VERSION 5.7 ;
  NOWIREEXTENSIONATPIN ON ;
  DIVIDERCHAR "/" ;
  BUSBITCHARS "[]" ;
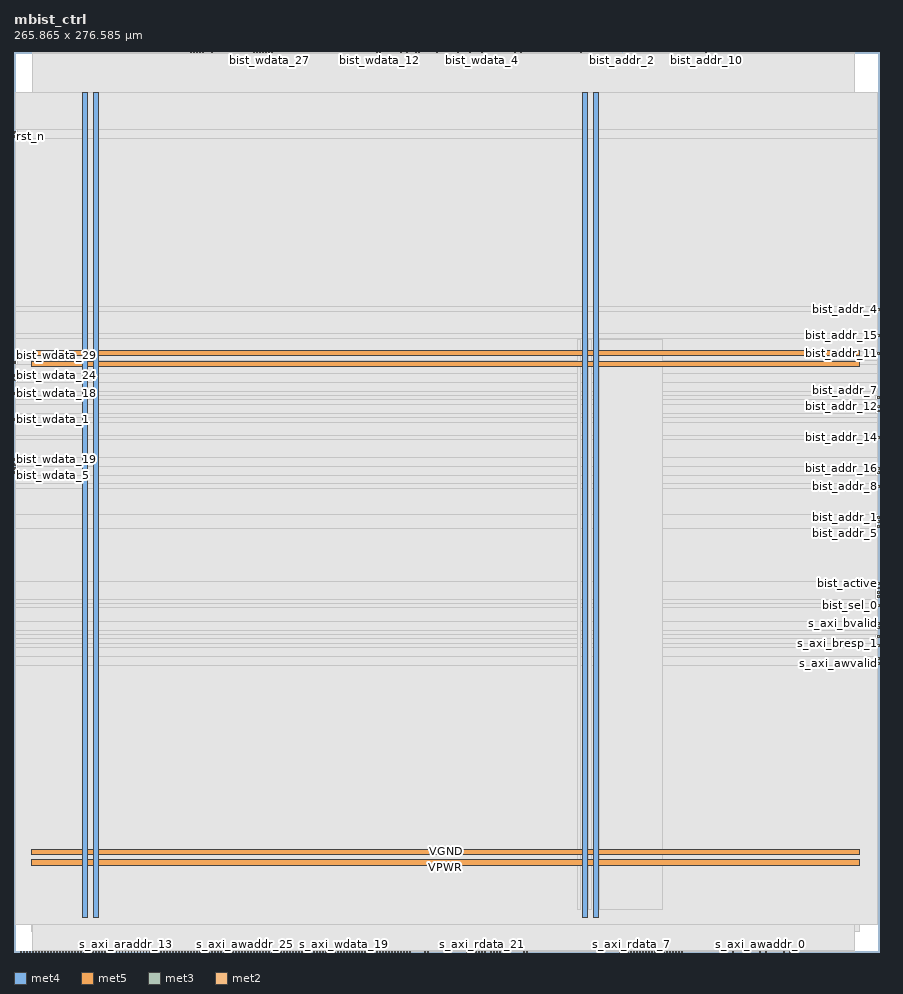
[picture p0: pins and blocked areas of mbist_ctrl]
MACRO mbist_ctrl
  CLASS BLOCK ;
  FOREIGN mbist_ctrl ;
  ORIGIN 0.000 0.000 ;
  SIZE 265.865 BY 276.585 ;
  PIN VGND
    DIRECTION INOUT ;
    USE GROUND ;
    PORT
      LAYER met4 ;
        RECT 24.340 10.640 25.940 264.080 ;
    END
    PORT
      LAYER met4 ;
        RECT 177.940 10.640 179.540 264.080 ;
    END
    PORT
      LAYER met5 ;
        RECT 5.520 30.030 259.900 31.630 ;
    END
    PORT
      LAYER met5 ;
        RECT 5.520 183.210 259.900 184.810 ;
    END
  END VGND
  PIN VPWR
    DIRECTION INOUT ;
    USE POWER ;
    PORT
      LAYER met4 ;
        RECT 21.040 10.640 22.640 264.080 ;
    END
    PORT
      LAYER met4 ;
        RECT 174.640 10.640 176.240 264.080 ;
    END
    PORT
      LAYER met5 ;
        RECT 5.520 26.730 259.900 28.330 ;
    END
    PORT
      LAYER met5 ;
        RECT 5.520 179.910 259.900 181.510 ;
    END
  END VPWR
  PIN bist_active
    DIRECTION OUTPUT ;
    USE SIGNAL ;
    ANTENNAGATEAREA 0.434700 ;
    ANTENNADIFFAREA 1.137600 ;
    PORT
      LAYER met3 ;
        RECT 265.265 112.920 265.865 113.520 ;
    END
  END bist_active
  PIN bist_addr_0
    DIRECTION OUTPUT ;
    USE SIGNAL ;
    ANTENNAGATEAREA 0.434700 ;
    ANTENNADIFFAREA 1.137600 ;
    PORT
      LAYER met3 ;
        RECT 265.265 146.920 265.865 147.520 ;
    END
  END bist_addr_0
  PIN bist_addr_1
    DIRECTION OUTPUT ;
    USE SIGNAL ;
    ANTENNAGATEAREA 0.434700 ;
    ANTENNADIFFAREA 1.137600 ;
    PORT
      LAYER met3 ;
        RECT 265.265 133.320 265.865 133.920 ;
    END
  END bist_addr_1
  PIN bist_addr_10
    DIRECTION OUTPUT ;
    USE SIGNAL ;
    ANTENNAGATEAREA 0.434700 ;
    ANTENNADIFFAREA 1.137600 ;
    PORT
      LAYER met2 ;
        RECT 212.610 276.305 212.890 276.585 ;
    END
  END bist_addr_10
  PIN bist_addr_11
    DIRECTION OUTPUT ;
    USE SIGNAL ;
    ANTENNAGATEAREA 0.434700 ;
    ANTENNADIFFAREA 1.137600 ;
    PORT
      LAYER met3 ;
        RECT 265.265 183.640 265.865 184.240 ;
    END
  END bist_addr_11
  PIN bist_addr_12
    DIRECTION OUTPUT ;
    USE SIGNAL ;
    ANTENNAGATEAREA 0.434700 ;
    ANTENNADIFFAREA 1.137600 ;
    PORT
      LAYER met3 ;
        RECT 265.265 167.320 265.865 167.920 ;
    END
  END bist_addr_12
  PIN bist_addr_13
    DIRECTION OUTPUT ;
    USE SIGNAL ;
    ANTENNAGATEAREA 0.434700 ;
    ANTENNADIFFAREA 1.137600 ;
    PORT
      LAYER met3 ;
        RECT 265.265 131.960 265.865 132.560 ;
    END
  END bist_addr_13
  PIN bist_addr_14
    DIRECTION OUTPUT ;
    USE SIGNAL ;
    ANTENNAGATEAREA 0.434700 ;
    ANTENNADIFFAREA 1.137600 ;
    PORT
      LAYER met3 ;
        RECT 265.265 157.800 265.865 158.400 ;
    END
  END bist_addr_14
  PIN bist_addr_15
    DIRECTION OUTPUT ;
    USE SIGNAL ;
    ANTENNAGATEAREA 0.434700 ;
    ANTENNADIFFAREA 1.137600 ;
    PORT
      LAYER met3 ;
        RECT 265.265 189.080 265.865 189.680 ;
    END
  END bist_addr_15
  PIN bist_addr_16
    DIRECTION OUTPUT ;
    USE SIGNAL ;
    ANTENNAGATEAREA 0.434700 ;
    ANTENNADIFFAREA 1.137600 ;
    PORT
      LAYER met3 ;
        RECT 265.265 148.280 265.865 148.880 ;
    END
  END bist_addr_16
  PIN bist_addr_17
    DIRECTION OUTPUT ;
    USE SIGNAL ;
    ANTENNAGATEAREA 0.434700 ;
    ANTENNADIFFAREA 1.137600 ;
    PORT
      LAYER met2 ;
        RECT 155.570 276.305 155.850 276.585 ;
    END
  END bist_addr_17
  PIN bist_addr_2
    DIRECTION OUTPUT ;
    USE SIGNAL ;
    ANTENNAGATEAREA 0.434700 ;
    ANTENNADIFFAREA 1.137600 ;
    PORT
      LAYER met2 ;
        RECT 186.850 276.305 187.130 276.585 ;
    END
  END bist_addr_2
  PIN bist_addr_3
    DIRECTION OUTPUT ;
    USE SIGNAL ;
    ANTENNAGATEAREA 0.434700 ;
    ANTENNADIFFAREA 1.137600 ;
    PORT
      LAYER met3 ;
        RECT 265.265 165.960 265.865 166.560 ;
    END
  END bist_addr_3
  PIN bist_addr_4
    DIRECTION OUTPUT ;
    USE SIGNAL ;
    ANTENNAGATEAREA 0.434700 ;
    ANTENNADIFFAREA 1.137600 ;
    PORT
      LAYER met3 ;
        RECT 265.265 197.240 265.865 197.840 ;
    END
  END bist_addr_4
  PIN bist_addr_5
    DIRECTION OUTPUT ;
    USE SIGNAL ;
    ANTENNAGATEAREA 0.434700 ;
    ANTENNADIFFAREA 1.137600 ;
    PORT
      LAYER met3 ;
        RECT 265.265 130.600 265.865 131.200 ;
    END
  END bist_addr_5
  PIN bist_addr_6
    DIRECTION OUTPUT ;
    USE SIGNAL ;
    ANTENNAGATEAREA 0.434700 ;
    ANTENNADIFFAREA 1.137600 ;
    PORT
      LAYER met2 ;
        RECT 153.730 276.305 154.010 276.585 ;
    END
  END bist_addr_6
  PIN bist_addr_7
    DIRECTION OUTPUT ;
    USE SIGNAL ;
    ANTENNAGATEAREA 0.434700 ;
    ANTENNADIFFAREA 1.137600 ;
    PORT
      LAYER met3 ;
        RECT 265.265 170.040 265.865 170.640 ;
    END
  END bist_addr_7
  PIN bist_addr_8
    DIRECTION OUTPUT ;
    USE SIGNAL ;
    ANTENNAGATEAREA 0.434700 ;
    ANTENNADIFFAREA 1.137600 ;
    PORT
      LAYER met3 ;
        RECT 265.265 142.840 265.865 143.440 ;
    END
  END bist_addr_8
  PIN bist_addr_9
    DIRECTION OUTPUT ;
    USE SIGNAL ;
    ANTENNAGATEAREA 0.434700 ;
    ANTENNADIFFAREA 1.137600 ;
    PORT
      LAYER met2 ;
        RECT 173.970 276.305 174.250 276.585 ;
    END
  END bist_addr_9
  PIN bist_en
    DIRECTION OUTPUT ;
    USE SIGNAL ;
    ANTENNAGATEAREA 0.434700 ;
    ANTENNADIFFAREA 1.137600 ;
    PORT
      LAYER met2 ;
        RECT 127.050 0.000 127.330 0.280 ;
    END
  END bist_en
  PIN bist_rdata_0
    DIRECTION INPUT ;
    USE SIGNAL ;
    PORT
      LAYER met2 ;
        RECT 1.930 0.000 2.210 0.280 ;
    END
  END bist_rdata_0
  PIN bist_rdata_1
    DIRECTION INPUT ;
    USE SIGNAL ;
    PORT
      LAYER met2 ;
        RECT 2.850 0.000 3.130 0.280 ;
    END
  END bist_rdata_1
  PIN bist_rdata_10
    DIRECTION INPUT ;
    USE SIGNAL ;
    PORT
      LAYER met2 ;
        RECT 3.770 0.000 4.050 0.280 ;
    END
  END bist_rdata_10
  PIN bist_rdata_11
    DIRECTION INPUT ;
    USE SIGNAL ;
    PORT
      LAYER met2 ;
        RECT 4.690 0.000 4.970 0.280 ;
    END
  END bist_rdata_11
  PIN bist_rdata_12
    DIRECTION INPUT ;
    USE SIGNAL ;
    PORT
      LAYER met2 ;
        RECT 5.610 0.000 5.890 0.280 ;
    END
  END bist_rdata_12
  PIN bist_rdata_13
    DIRECTION INPUT ;
    USE SIGNAL ;
    PORT
      LAYER met2 ;
        RECT 6.530 0.000 6.810 0.280 ;
    END
  END bist_rdata_13
  PIN bist_rdata_14
    DIRECTION INPUT ;
    USE SIGNAL ;
    PORT
      LAYER met2 ;
        RECT 7.450 0.000 7.730 0.280 ;
    END
  END bist_rdata_14
  PIN bist_rdata_15
    DIRECTION INPUT ;
    USE SIGNAL ;
    PORT
      LAYER met2 ;
        RECT 8.370 0.000 8.650 0.280 ;
    END
  END bist_rdata_15
  PIN bist_rdata_16
    DIRECTION INPUT ;
    USE SIGNAL ;
    PORT
      LAYER met2 ;
        RECT 9.290 0.000 9.570 0.280 ;
    END
  END bist_rdata_16
  PIN bist_rdata_17
    DIRECTION INPUT ;
    USE SIGNAL ;
    PORT
      LAYER met2 ;
        RECT 10.210 0.000 10.490 0.280 ;
    END
  END bist_rdata_17
  PIN bist_rdata_18
    DIRECTION INPUT ;
    USE SIGNAL ;
    PORT
      LAYER met2 ;
        RECT 11.130 0.000 11.410 0.280 ;
    END
  END bist_rdata_18
  PIN bist_rdata_19
    DIRECTION INPUT ;
    USE SIGNAL ;
    PORT
      LAYER met2 ;
        RECT 12.050 0.000 12.330 0.280 ;
    END
  END bist_rdata_19
  PIN bist_rdata_2
    DIRECTION INPUT ;
    USE SIGNAL ;
    PORT
      LAYER met2 ;
        RECT 12.970 0.000 13.250 0.280 ;
    END
  END bist_rdata_2
  PIN bist_rdata_20
    DIRECTION INPUT ;
    USE SIGNAL ;
    PORT
      LAYER met2 ;
        RECT 13.890 0.000 14.170 0.280 ;
    END
  END bist_rdata_20
  PIN bist_rdata_21
    DIRECTION INPUT ;
    USE SIGNAL ;
    PORT
      LAYER met2 ;
        RECT 14.810 0.000 15.090 0.280 ;
    END
  END bist_rdata_21
  PIN bist_rdata_22
    DIRECTION INPUT ;
    USE SIGNAL ;
    PORT
      LAYER met2 ;
        RECT 15.730 0.000 16.010 0.280 ;
    END
  END bist_rdata_22
  PIN bist_rdata_23
    DIRECTION INPUT ;
    USE SIGNAL ;
    PORT
      LAYER met2 ;
        RECT 16.650 0.000 16.930 0.280 ;
    END
  END bist_rdata_23
  PIN bist_rdata_24
    DIRECTION INPUT ;
    USE SIGNAL ;
    PORT
      LAYER met2 ;
        RECT 17.570 0.000 17.850 0.280 ;
    END
  END bist_rdata_24
  PIN bist_rdata_25
    DIRECTION INPUT ;
    USE SIGNAL ;
    PORT
      LAYER met2 ;
        RECT 18.490 0.000 18.770 0.280 ;
    END
  END bist_rdata_25
  PIN bist_rdata_26
    DIRECTION INPUT ;
    USE SIGNAL ;
    PORT
      LAYER met2 ;
        RECT 19.410 0.000 19.690 0.280 ;
    END
  END bist_rdata_26
  PIN bist_rdata_27
    DIRECTION INPUT ;
    USE SIGNAL ;
    PORT
      LAYER met2 ;
        RECT 20.330 0.000 20.610 0.280 ;
    END
  END bist_rdata_27
  PIN bist_rdata_28
    DIRECTION INPUT ;
    USE SIGNAL ;
    PORT
      LAYER met2 ;
        RECT 21.250 0.000 21.530 0.280 ;
    END
  END bist_rdata_28
  PIN bist_rdata_29
    DIRECTION INPUT ;
    USE SIGNAL ;
    PORT
      LAYER met2 ;
        RECT 22.170 0.000 22.450 0.280 ;
    END
  END bist_rdata_29
  PIN bist_rdata_3
    DIRECTION INPUT ;
    USE SIGNAL ;
    PORT
      LAYER met2 ;
        RECT 23.090 0.000 23.370 0.280 ;
    END
  END bist_rdata_3
  PIN bist_rdata_30
    DIRECTION INPUT ;
    USE SIGNAL ;
    PORT
      LAYER met2 ;
        RECT 24.010 0.000 24.290 0.280 ;
    END
  END bist_rdata_30
  PIN bist_rdata_31
    DIRECTION INPUT ;
    USE SIGNAL ;
    PORT
      LAYER met2 ;
        RECT 24.930 0.000 25.210 0.280 ;
    END
  END bist_rdata_31
  PIN bist_rdata_4
    DIRECTION INPUT ;
    USE SIGNAL ;
    PORT
      LAYER met2 ;
        RECT 25.850 0.000 26.130 0.280 ;
    END
  END bist_rdata_4
  PIN bist_rdata_5
    DIRECTION INPUT ;
    USE SIGNAL ;
    PORT
      LAYER met2 ;
        RECT 26.770 0.000 27.050 0.280 ;
    END
  END bist_rdata_5
  PIN bist_rdata_6
    DIRECTION INPUT ;
    USE SIGNAL ;
    PORT
      LAYER met2 ;
        RECT 27.690 0.000 27.970 0.280 ;
    END
  END bist_rdata_6
  PIN bist_rdata_7
    DIRECTION INPUT ;
    USE SIGNAL ;
    PORT
      LAYER met2 ;
        RECT 28.610 0.000 28.890 0.280 ;
    END
  END bist_rdata_7
  PIN bist_rdata_8
    DIRECTION INPUT ;
    USE SIGNAL ;
    PORT
      LAYER met2 ;
        RECT 29.530 0.000 29.810 0.280 ;
    END
  END bist_rdata_8
  PIN bist_rdata_9
    DIRECTION INPUT ;
    USE SIGNAL ;
    PORT
      LAYER met2 ;
        RECT 30.450 0.000 30.730 0.280 ;
    END
  END bist_rdata_9
  PIN bist_sel_0
    DIRECTION OUTPUT ;
    USE SIGNAL ;
    ANTENNAGATEAREA 0.434700 ;
    ANTENNADIFFAREA 1.137600 ;
    PORT
      LAYER met3 ;
        RECT 265.265 106.120 265.865 106.720 ;
    END
  END bist_sel_0
  PIN bist_sel_1
    DIRECTION OUTPUT ;
    USE SIGNAL ;
    ANTENNAGATEAREA 0.434700 ;
    ANTENNADIFFAREA 1.137600 ;
    PORT
      LAYER met3 ;
        RECT 265.265 110.200 265.865 110.800 ;
    END
  END bist_sel_1
  PIN bist_sel_2
    DIRECTION OUTPUT ;
    USE SIGNAL ;
    ANTENNAGATEAREA 0.434700 ;
    ANTENNADIFFAREA 1.137600 ;
    PORT
      LAYER met3 ;
        RECT 265.265 108.840 265.865 109.440 ;
    END
  END bist_sel_2
  PIN bist_sel_3
    DIRECTION OUTPUT ;
    USE SIGNAL ;
    ANTENNAGATEAREA 0.434700 ;
    ANTENNADIFFAREA 1.137600 ;
    PORT
      LAYER met3 ;
        RECT 265.265 111.560 265.865 112.160 ;
    END
  END bist_sel_3
  PIN bist_wdata_0
    DIRECTION OUTPUT ;
    USE SIGNAL ;
    ANTENNAGATEAREA 0.434700 ;
    ANTENNADIFFAREA 1.137600 ;
    PORT
      LAYER met2 ;
        RECT 129.810 276.305 130.090 276.585 ;
    END
  END bist_wdata_0
  PIN bist_wdata_1
    DIRECTION OUTPUT ;
    USE SIGNAL ;
    ANTENNAGATEAREA 0.434700 ;
    ANTENNADIFFAREA 1.137600 ;
    PORT
      LAYER met3 ;
        RECT 0.000 163.240 0.600 163.840 ;
    END
  END bist_wdata_1
  PIN bist_wdata_10
    DIRECTION OUTPUT ;
    USE SIGNAL ;
    ANTENNAGATEAREA 0.434700 ;
    ANTENNADIFFAREA 1.137600 ;
    PORT
      LAYER met2 ;
        RECT 73.690 276.305 73.970 276.585 ;
    END
  END bist_wdata_10
  PIN bist_wdata_11
    DIRECTION OUTPUT ;
    USE SIGNAL ;
    ANTENNAGATEAREA 0.434700 ;
    ANTENNADIFFAREA 1.137600 ;
    PORT
      LAYER met2 ;
        RECT 136.250 276.305 136.530 276.585 ;
    END
  END bist_wdata_11
  PIN bist_wdata_12
    DIRECTION OUTPUT ;
    USE SIGNAL ;
    ANTENNAGATEAREA 0.434700 ;
    ANTENNADIFFAREA 1.137600 ;
    PORT
      LAYER met2 ;
        RECT 112.330 276.305 112.610 276.585 ;
    END
  END bist_wdata_12
  PIN bist_wdata_13
    DIRECTION OUTPUT ;
    USE SIGNAL ;
    ANTENNAGATEAREA 0.434700 ;
    ANTENNADIFFAREA 1.137600 ;
    PORT
      LAYER met2 ;
        RECT 74.610 276.305 74.890 276.585 ;
    END
  END bist_wdata_13
  PIN bist_wdata_14
    DIRECTION OUTPUT ;
    USE SIGNAL ;
    ANTENNAGATEAREA 0.434700 ;
    ANTENNADIFFAREA 1.137600 ;
    PORT
      LAYER met3 ;
        RECT 0.000 149.640 0.600 150.240 ;
    END
  END bist_wdata_14
  PIN bist_wdata_15
    DIRECTION OUTPUT ;
    USE SIGNAL ;
    ANTENNAGATEAREA 0.434700 ;
    ANTENNADIFFAREA 1.137600 ;
    PORT
      LAYER met2 ;
        RECT 79.210 276.305 79.490 276.585 ;
    END
  END bist_wdata_15
  PIN bist_wdata_16
    DIRECTION OUTPUT ;
    USE SIGNAL ;
    ANTENNAGATEAREA 0.434700 ;
    ANTENNADIFFAREA 1.137600 ;
    PORT
      LAYER met2 ;
        RECT 56.210 276.305 56.490 276.585 ;
    END
  END bist_wdata_16
  PIN bist_wdata_17
    DIRECTION OUTPUT ;
    USE SIGNAL ;
    ANTENNAGATEAREA 0.434700 ;
    ANTENNADIFFAREA 1.137600 ;
    PORT
      LAYER met2 ;
        RECT 60.810 276.305 61.090 276.585 ;
    END
  END bist_wdata_17
  PIN bist_wdata_18
    DIRECTION OUTPUT ;
    USE SIGNAL ;
    ANTENNAGATEAREA 0.434700 ;
    ANTENNADIFFAREA 1.137600 ;
    PORT
      LAYER met3 ;
        RECT 0.000 171.400 0.600 172.000 ;
    END
  END bist_wdata_18
  PIN bist_wdata_19
    DIRECTION OUTPUT ;
    USE SIGNAL ;
    ANTENNAGATEAREA 0.434700 ;
    ANTENNADIFFAREA 1.137600 ;
    PORT
      LAYER met3 ;
        RECT 0.000 151.000 0.600 151.600 ;
    END
  END bist_wdata_19
  PIN bist_wdata_2
    DIRECTION OUTPUT ;
    USE SIGNAL ;
    ANTENNAGATEAREA 0.434700 ;
    ANTENNADIFFAREA 1.137600 ;
    PORT
      LAYER met2 ;
        RECT 124.290 276.305 124.570 276.585 ;
    END
  END bist_wdata_2
  PIN bist_wdata_20
    DIRECTION OUTPUT ;
    USE SIGNAL ;
    ANTENNAGATEAREA 0.434700 ;
    ANTENNADIFFAREA 1.137600 ;
    PORT
      LAYER met2 ;
        RECT 75.530 276.305 75.810 276.585 ;
    END
  END bist_wdata_20
  PIN bist_wdata_21
    DIRECTION OUTPUT ;
    USE SIGNAL ;
    ANTENNAGATEAREA 0.434700 ;
    ANTENNADIFFAREA 1.137600 ;
    PORT
      LAYER met2 ;
        RECT 76.450 276.305 76.730 276.585 ;
    END
  END bist_wdata_21
  PIN bist_wdata_22
    DIRECTION OUTPUT ;
    USE SIGNAL ;
    ANTENNAGATEAREA 0.434700 ;
    ANTENNADIFFAREA 1.137600 ;
    PORT
      LAYER met2 ;
        RECT 55.290 276.305 55.570 276.585 ;
    END
  END bist_wdata_22
  PIN bist_wdata_23
    DIRECTION OUTPUT ;
    USE SIGNAL ;
    ANTENNAGATEAREA 0.434700 ;
    ANTENNADIFFAREA 1.137600 ;
    PORT
      LAYER met2 ;
        RECT 120.610 276.305 120.890 276.585 ;
    END
  END bist_wdata_23
  PIN bist_wdata_24
    DIRECTION OUTPUT ;
    USE SIGNAL ;
    ANTENNAGATEAREA 0.434700 ;
    ANTENNADIFFAREA 1.137600 ;
    PORT
      LAYER met3 ;
        RECT 0.000 176.840 0.600 177.440 ;
    END
  END bist_wdata_24
  PIN bist_wdata_25
    DIRECTION OUTPUT ;
    USE SIGNAL ;
    ANTENNAGATEAREA 0.434700 ;
    ANTENNADIFFAREA 1.137600 ;
    PORT
      LAYER met2 ;
        RECT 54.370 276.305 54.650 276.585 ;
    END
  END bist_wdata_25
  PIN bist_wdata_26
    DIRECTION OUTPUT ;
    USE SIGNAL ;
    ANTENNAGATEAREA 0.434700 ;
    ANTENNADIFFAREA 1.137600 ;
    PORT
      LAYER met3 ;
        RECT 0.000 146.920 0.600 147.520 ;
    END
  END bist_wdata_26
  PIN bist_wdata_27
    DIRECTION OUTPUT ;
    USE SIGNAL ;
    ANTENNAGATEAREA 0.434700 ;
    ANTENNADIFFAREA 1.137600 ;
    PORT
      LAYER met2 ;
        RECT 78.290 276.305 78.570 276.585 ;
    END
  END bist_wdata_27
  PIN bist_wdata_28
    DIRECTION OUTPUT ;
    USE SIGNAL ;
    ANTENNAGATEAREA 0.434700 ;
    ANTENNADIFFAREA 1.137600 ;
    PORT
      LAYER met2 ;
        RECT 57.130 276.305 57.410 276.585 ;
    END
  END bist_wdata_28
  PIN bist_wdata_29
    DIRECTION OUTPUT ;
    USE SIGNAL ;
    ANTENNAGATEAREA 0.434700 ;
    ANTENNADIFFAREA 1.137600 ;
    PORT
      LAYER met3 ;
        RECT 0.000 180.920 0.600 181.520 ;
    END
  END bist_wdata_29
  PIN bist_wdata_3
    DIRECTION OUTPUT ;
    USE SIGNAL ;
    ANTENNAGATEAREA 0.434700 ;
    ANTENNADIFFAREA 1.137600 ;
    PORT
      LAYER met2 ;
        RECT 118.770 276.305 119.050 276.585 ;
    END
  END bist_wdata_3
  PIN bist_wdata_30
    DIRECTION OUTPUT ;
    USE SIGNAL ;
    ANTENNAGATEAREA 0.434700 ;
    ANTENNADIFFAREA 1.137600 ;
    PORT
      LAYER met2 ;
        RECT 139.930 276.305 140.210 276.585 ;
    END
  END bist_wdata_30
  PIN bist_wdata_31
    DIRECTION OUTPUT ;
    USE SIGNAL ;
    ANTENNAGATEAREA 0.434700 ;
    ANTENNADIFFAREA 1.137600 ;
    PORT
      LAYER met2 ;
        RECT 77.370 276.305 77.650 276.585 ;
    END
  END bist_wdata_31
  PIN bist_wdata_4
    DIRECTION OUTPUT ;
    USE SIGNAL ;
    ANTENNAGATEAREA 0.434700 ;
    ANTENNADIFFAREA 1.137600 ;
    PORT
      LAYER met2 ;
        RECT 143.610 276.305 143.890 276.585 ;
    END
  END bist_wdata_4
  PIN bist_wdata_5
    DIRECTION OUTPUT ;
    USE SIGNAL ;
    ANTENNAGATEAREA 0.434700 ;
    ANTENNADIFFAREA 1.137600 ;
    PORT
      LAYER met3 ;
        RECT 0.000 148.280 0.600 148.880 ;
    END
  END bist_wdata_5
  PIN bist_wdata_6
    DIRECTION OUTPUT ;
    USE SIGNAL ;
    ANTENNAGATEAREA 0.434700 ;
    ANTENNADIFFAREA 1.137600 ;
    PORT
      LAYER met2 ;
        RECT 123.370 276.305 123.650 276.585 ;
    END
  END bist_wdata_6
  PIN bist_wdata_7
    DIRECTION OUTPUT ;
    USE SIGNAL ;
    ANTENNAGATEAREA 0.434700 ;
    ANTENNADIFFAREA 1.137600 ;
    PORT
      LAYER met3 ;
        RECT 0.000 175.480 0.600 176.080 ;
    END
  END bist_wdata_7
  PIN bist_wdata_8
    DIRECTION OUTPUT ;
    USE SIGNAL ;
    ANTENNAGATEAREA 0.434700 ;
    ANTENNADIFFAREA 1.137600 ;
    PORT
      LAYER met2 ;
        RECT 58.050 276.305 58.330 276.585 ;
    END
  END bist_wdata_8
  PIN bist_wdata_9
    DIRECTION OUTPUT ;
    USE SIGNAL ;
    ANTENNAGATEAREA 0.434700 ;
    ANTENNADIFFAREA 1.137600 ;
    PORT
      LAYER met2 ;
        RECT 111.410 276.305 111.690 276.585 ;
    END
  END bist_wdata_9
  PIN bist_we
    DIRECTION OUTPUT ;
    USE SIGNAL ;
    ANTENNAGATEAREA 0.434700 ;
    ANTENNADIFFAREA 1.137600 ;
    PORT
      LAYER met2 ;
        RECT 126.130 0.000 126.410 0.280 ;
    END
  END bist_we
  PIN clk
    DIRECTION INPUT ;
    USE SIGNAL ;
    ANTENNAGATEAREA 1.286700 ;
    ANTENNADIFFAREA 0.434700 ;
    PORT
      LAYER met3 ;
        RECT 0.000 251.640 0.600 252.240 ;
    END
  END clk
  PIN rst_n
    DIRECTION INPUT ;
    USE SIGNAL ;
    ANTENNAGATEAREA 0.647700 ;
    ANTENNADIFFAREA 0.434700 ;
    PORT
      LAYER met3 ;
        RECT 0.000 250.280 0.600 250.880 ;
    END
  END rst_n
  PIN s_axi_araddr_0
    DIRECTION INPUT ;
    USE SIGNAL ;
    ANTENNAGATEAREA 0.647700 ;
    ANTENNADIFFAREA 0.434700 ;
    PORT
      LAYER met2 ;
        RECT 196.970 0.000 197.250 0.280 ;
    END
  END s_axi_araddr_0
  PIN s_axi_araddr_1
    DIRECTION INPUT ;
    USE SIGNAL ;
    ANTENNAGATEAREA 0.647700 ;
    ANTENNADIFFAREA 0.434700 ;
    PORT
      LAYER met2 ;
        RECT 192.370 0.000 192.650 0.280 ;
    END
  END s_axi_araddr_1
  PIN s_axi_araddr_10
    DIRECTION INPUT ;
    USE SIGNAL ;
    PORT
      LAYER met2 ;
        RECT 31.370 0.000 31.650 0.280 ;
    END
  END s_axi_araddr_10
  PIN s_axi_araddr_11
    DIRECTION INPUT ;
    USE SIGNAL ;
    PORT
      LAYER met2 ;
        RECT 32.290 0.000 32.570 0.280 ;
    END
  END s_axi_araddr_11
  PIN s_axi_araddr_12
    DIRECTION INPUT ;
    USE SIGNAL ;
    PORT
      LAYER met2 ;
        RECT 33.210 0.000 33.490 0.280 ;
    END
  END s_axi_araddr_12
  PIN s_axi_araddr_13
    DIRECTION INPUT ;
    USE SIGNAL ;
    PORT
      LAYER met2 ;
        RECT 34.130 0.000 34.410 0.280 ;
    END
  END s_axi_araddr_13
  PIN s_axi_araddr_14
    DIRECTION INPUT ;
    USE SIGNAL ;
    PORT
      LAYER met2 ;
        RECT 35.050 0.000 35.330 0.280 ;
    END
  END s_axi_araddr_14
  PIN s_axi_araddr_15
    DIRECTION INPUT ;
    USE SIGNAL ;
    PORT
      LAYER met2 ;
        RECT 35.970 0.000 36.250 0.280 ;
    END
  END s_axi_araddr_15
  PIN s_axi_araddr_16
    DIRECTION INPUT ;
    USE SIGNAL ;
    PORT
      LAYER met2 ;
        RECT 36.890 0.000 37.170 0.280 ;
    END
  END s_axi_araddr_16
  PIN s_axi_araddr_17
    DIRECTION INPUT ;
    USE SIGNAL ;
    PORT
      LAYER met2 ;
        RECT 37.810 0.000 38.090 0.280 ;
    END
  END s_axi_araddr_17
  PIN s_axi_araddr_18
    DIRECTION INPUT ;
    USE SIGNAL ;
    PORT
      LAYER met2 ;
        RECT 38.730 0.000 39.010 0.280 ;
    END
  END s_axi_araddr_18
  PIN s_axi_araddr_19
    DIRECTION INPUT ;
    USE SIGNAL ;
    PORT
      LAYER met2 ;
        RECT 39.650 0.000 39.930 0.280 ;
    END
  END s_axi_araddr_19
  PIN s_axi_araddr_2
    DIRECTION INPUT ;
    USE SIGNAL ;
    ANTENNAGATEAREA 0.647700 ;
    ANTENNADIFFAREA 0.434700 ;
    PORT
      LAYER met2 ;
        RECT 191.450 0.000 191.730 0.280 ;
    END
  END s_axi_araddr_2
  PIN s_axi_araddr_20
    DIRECTION INPUT ;
    USE SIGNAL ;
    PORT
      LAYER met2 ;
        RECT 40.570 0.000 40.850 0.280 ;
    END
  END s_axi_araddr_20
  PIN s_axi_araddr_21
    DIRECTION INPUT ;
    USE SIGNAL ;
    PORT
      LAYER met2 ;
        RECT 41.490 0.000 41.770 0.280 ;
    END
  END s_axi_araddr_21
  PIN s_axi_araddr_22
    DIRECTION INPUT ;
    USE SIGNAL ;
    PORT
      LAYER met2 ;
        RECT 42.410 0.000 42.690 0.280 ;
    END
  END s_axi_araddr_22
  PIN s_axi_araddr_23
    DIRECTION INPUT ;
    USE SIGNAL ;
    PORT
      LAYER met2 ;
        RECT 43.330 0.000 43.610 0.280 ;
    END
  END s_axi_araddr_23
  PIN s_axi_araddr_24
    DIRECTION INPUT ;
    USE SIGNAL ;
    PORT
      LAYER met2 ;
        RECT 44.250 0.000 44.530 0.280 ;
    END
  END s_axi_araddr_24
  PIN s_axi_araddr_25
    DIRECTION INPUT ;
    USE SIGNAL ;
    PORT
      LAYER met2 ;
        RECT 45.170 0.000 45.450 0.280 ;
    END
  END s_axi_araddr_25
  PIN s_axi_araddr_26
    DIRECTION INPUT ;
    USE SIGNAL ;
    PORT
      LAYER met2 ;
        RECT 46.090 0.000 46.370 0.280 ;
    END
  END s_axi_araddr_26
  PIN s_axi_araddr_27
    DIRECTION INPUT ;
    USE SIGNAL ;
    PORT
      LAYER met2 ;
        RECT 47.010 0.000 47.290 0.280 ;
    END
  END s_axi_araddr_27
  PIN s_axi_araddr_28
    DIRECTION INPUT ;
    USE SIGNAL ;
    PORT
      LAYER met2 ;
        RECT 47.930 0.000 48.210 0.280 ;
    END
  END s_axi_araddr_28
  PIN s_axi_araddr_29
    DIRECTION INPUT ;
    USE SIGNAL ;
    PORT
      LAYER met2 ;
        RECT 48.850 0.000 49.130 0.280 ;
    END
  END s_axi_araddr_29
  PIN s_axi_araddr_3
    DIRECTION INPUT ;
    USE SIGNAL ;
    ANTENNAGATEAREA 0.647700 ;
    ANTENNADIFFAREA 0.434700 ;
    PORT
      LAYER met2 ;
        RECT 186.850 0.000 187.130 0.280 ;
    END
  END s_axi_araddr_3
  PIN s_axi_araddr_30
    DIRECTION INPUT ;
    USE SIGNAL ;
    PORT
      LAYER met2 ;
        RECT 49.770 0.000 50.050 0.280 ;
    END
  END s_axi_araddr_30
  PIN s_axi_araddr_31
    DIRECTION INPUT ;
    USE SIGNAL ;
    PORT
      LAYER met2 ;
        RECT 50.690 0.000 50.970 0.280 ;
    END
  END s_axi_araddr_31
  PIN s_axi_araddr_4
    DIRECTION INPUT ;
    USE SIGNAL ;
    ANTENNAGATEAREA 0.647700 ;
    ANTENNADIFFAREA 0.434700 ;
    PORT
      LAYER met2 ;
        RECT 185.930 0.000 186.210 0.280 ;
    END
  END s_axi_araddr_4
  PIN s_axi_araddr_5
    DIRECTION INPUT ;
    USE SIGNAL ;
    PORT
      LAYER met2 ;
        RECT 51.610 0.000 51.890 0.280 ;
    END
  END s_axi_araddr_5
  PIN s_axi_araddr_6
    DIRECTION INPUT ;
    USE SIGNAL ;
    PORT
      LAYER met2 ;
        RECT 52.530 0.000 52.810 0.280 ;
    END
  END s_axi_araddr_6
  PIN s_axi_araddr_7
    DIRECTION INPUT ;
    USE SIGNAL ;
    PORT
      LAYER met2 ;
        RECT 53.450 0.000 53.730 0.280 ;
    END
  END s_axi_araddr_7
  PIN s_axi_araddr_8
    DIRECTION INPUT ;
    USE SIGNAL ;
    PORT
      LAYER met2 ;
        RECT 54.370 0.000 54.650 0.280 ;
    END
  END s_axi_araddr_8
  PIN s_axi_araddr_9
    DIRECTION INPUT ;
    USE SIGNAL ;
    PORT
      LAYER met2 ;
        RECT 55.290 0.000 55.570 0.280 ;
    END
  END s_axi_araddr_9
  PIN s_axi_arready
    DIRECTION OUTPUT ;
    USE SIGNAL ;
    PORT
      LAYER met2 ;
        RECT 56.210 0.000 56.490 0.280 ;
    END
  END s_axi_arready
  PIN s_axi_arvalid
    DIRECTION INPUT ;
    USE SIGNAL ;
    ANTENNAGATEAREA 0.647700 ;
    ANTENNADIFFAREA 0.434700 ;
    PORT
      LAYER met2 ;
        RECT 196.050 0.000 196.330 0.280 ;
    END
  END s_axi_arvalid
  PIN s_axi_awaddr_0
    DIRECTION INPUT ;
    USE SIGNAL ;
    ANTENNAGATEAREA 0.647700 ;
    ANTENNADIFFAREA 0.434700 ;
    PORT
      LAYER met2 ;
        RECT 229.170 0.000 229.450 0.280 ;
    END
  END s_axi_awaddr_0
  PIN s_axi_awaddr_1
    DIRECTION INPUT ;
    USE SIGNAL ;
    ANTENNAGATEAREA 0.647700 ;
    ANTENNADIFFAREA 0.434700 ;
    PORT
      LAYER met2 ;
        RECT 231.010 0.000 231.290 0.280 ;
    END
  END s_axi_awaddr_1
  PIN s_axi_awaddr_10
    DIRECTION INPUT ;
    USE SIGNAL ;
    PORT
      LAYER met2 ;
        RECT 57.130 0.000 57.410 0.280 ;
    END
  END s_axi_awaddr_10
  PIN s_axi_awaddr_11
    DIRECTION INPUT ;
    USE SIGNAL ;
    PORT
      LAYER met2 ;
        RECT 58.050 0.000 58.330 0.280 ;
    END
  END s_axi_awaddr_11
  PIN s_axi_awaddr_12
    DIRECTION INPUT ;
    USE SIGNAL ;
    PORT
      LAYER met2 ;
        RECT 58.970 0.000 59.250 0.280 ;
    END
  END s_axi_awaddr_12
  PIN s_axi_awaddr_13
    DIRECTION INPUT ;
    USE SIGNAL ;
    PORT
      LAYER met2 ;
        RECT 59.890 0.000 60.170 0.280 ;
    END
  END s_axi_awaddr_13
  PIN s_axi_awaddr_14
    DIRECTION INPUT ;
    USE SIGNAL ;
    PORT
      LAYER met2 ;
        RECT 60.810 0.000 61.090 0.280 ;
    END
  END s_axi_awaddr_14
  PIN s_axi_awaddr_15
    DIRECTION INPUT ;
    USE SIGNAL ;
    PORT
      LAYER met2 ;
        RECT 61.730 0.000 62.010 0.280 ;
    END
  END s_axi_awaddr_15
  PIN s_axi_awaddr_16
    DIRECTION INPUT ;
    USE SIGNAL ;
    PORT
      LAYER met2 ;
        RECT 62.650 0.000 62.930 0.280 ;
    END
  END s_axi_awaddr_16
  PIN s_axi_awaddr_17
    DIRECTION INPUT ;
    USE SIGNAL ;
    PORT
      LAYER met2 ;
        RECT 63.570 0.000 63.850 0.280 ;
    END
  END s_axi_awaddr_17
  PIN s_axi_awaddr_18
    DIRECTION INPUT ;
    USE SIGNAL ;
    PORT
      LAYER met2 ;
        RECT 64.490 0.000 64.770 0.280 ;
    END
  END s_axi_awaddr_18
  PIN s_axi_awaddr_19
    DIRECTION INPUT ;
    USE SIGNAL ;
    PORT
      LAYER met2 ;
        RECT 65.410 0.000 65.690 0.280 ;
    END
  END s_axi_awaddr_19
  PIN s_axi_awaddr_2
    DIRECTION INPUT ;
    USE SIGNAL ;
    ANTENNAGATEAREA 0.647700 ;
    ANTENNADIFFAREA 0.434700 ;
    PORT
      LAYER met2 ;
        RECT 236.530 0.000 236.810 0.280 ;
    END
  END s_axi_awaddr_2
  PIN s_axi_awaddr_20
    DIRECTION INPUT ;
    USE SIGNAL ;
    PORT
      LAYER met2 ;
        RECT 66.330 0.000 66.610 0.280 ;
    END
  END s_axi_awaddr_20
  PIN s_axi_awaddr_21
    DIRECTION INPUT ;
    USE SIGNAL ;
    PORT
      LAYER met2 ;
        RECT 67.250 0.000 67.530 0.280 ;
    END
  END s_axi_awaddr_21
  PIN s_axi_awaddr_22
    DIRECTION INPUT ;
    USE SIGNAL ;
    PORT
      LAYER met2 ;
        RECT 68.170 0.000 68.450 0.280 ;
    END
  END s_axi_awaddr_22
  PIN s_axi_awaddr_23
    DIRECTION INPUT ;
    USE SIGNAL ;
    PORT
      LAYER met2 ;
        RECT 69.090 0.000 69.370 0.280 ;
    END
  END s_axi_awaddr_23
  PIN s_axi_awaddr_24
    DIRECTION INPUT ;
    USE SIGNAL ;
    PORT
      LAYER met2 ;
        RECT 70.010 0.000 70.290 0.280 ;
    END
  END s_axi_awaddr_24
  PIN s_axi_awaddr_25
    DIRECTION INPUT ;
    USE SIGNAL ;
    PORT
      LAYER met2 ;
        RECT 70.930 0.000 71.210 0.280 ;
    END
  END s_axi_awaddr_25
  PIN s_axi_awaddr_26
    DIRECTION INPUT ;
    USE SIGNAL ;
    PORT
      LAYER met2 ;
        RECT 71.850 0.000 72.130 0.280 ;
    END
  END s_axi_awaddr_26
  PIN s_axi_awaddr_27
    DIRECTION INPUT ;
    USE SIGNAL ;
    PORT
      LAYER met2 ;
        RECT 72.770 0.000 73.050 0.280 ;
    END
  END s_axi_awaddr_27
  PIN s_axi_awaddr_28
    DIRECTION INPUT ;
    USE SIGNAL ;
    PORT
      LAYER met2 ;
        RECT 73.690 0.000 73.970 0.280 ;
    END
  END s_axi_awaddr_28
  PIN s_axi_awaddr_29
    DIRECTION INPUT ;
    USE SIGNAL ;
    PORT
      LAYER met2 ;
        RECT 74.610 0.000 74.890 0.280 ;
    END
  END s_axi_awaddr_29
  PIN s_axi_awaddr_3
    DIRECTION INPUT ;
    USE SIGNAL ;
    ANTENNAGATEAREA 0.647700 ;
    ANTENNADIFFAREA 0.434700 ;
    PORT
      LAYER met2 ;
        RECT 220.890 0.000 221.170 0.280 ;
    END
  END s_axi_awaddr_3
  PIN s_axi_awaddr_30
    DIRECTION INPUT ;
    USE SIGNAL ;
    PORT
      LAYER met2 ;
        RECT 75.530 0.000 75.810 0.280 ;
    END
  END s_axi_awaddr_30
  PIN s_axi_awaddr_31
    DIRECTION INPUT ;
    USE SIGNAL ;
    PORT
      LAYER met2 ;
        RECT 76.450 0.000 76.730 0.280 ;
    END
  END s_axi_awaddr_31
  PIN s_axi_awaddr_4
    DIRECTION INPUT ;
    USE SIGNAL ;
    ANTENNAGATEAREA 0.647700 ;
    ANTENNADIFFAREA 0.434700 ;
    PORT
      LAYER met2 ;
        RECT 238.370 0.000 238.650 0.280 ;
    END
  END s_axi_awaddr_4
  PIN s_axi_awaddr_5
    DIRECTION INPUT ;
    USE SIGNAL ;
    PORT
      LAYER met2 ;
        RECT 77.370 0.000 77.650 0.280 ;
    END
  END s_axi_awaddr_5
  PIN s_axi_awaddr_6
    DIRECTION INPUT ;
    USE SIGNAL ;
    PORT
      LAYER met2 ;
        RECT 78.290 0.000 78.570 0.280 ;
    END
  END s_axi_awaddr_6
  PIN s_axi_awaddr_7
    DIRECTION INPUT ;
    USE SIGNAL ;
    PORT
      LAYER met2 ;
        RECT 79.210 0.000 79.490 0.280 ;
    END
  END s_axi_awaddr_7
  PIN s_axi_awaddr_8
    DIRECTION INPUT ;
    USE SIGNAL ;
    PORT
      LAYER met2 ;
        RECT 80.130 0.000 80.410 0.280 ;
    END
  END s_axi_awaddr_8
  PIN s_axi_awaddr_9
    DIRECTION INPUT ;
    USE SIGNAL ;
    PORT
      LAYER met2 ;
        RECT 81.050 0.000 81.330 0.280 ;
    END
  END s_axi_awaddr_9
  PIN s_axi_awready
    DIRECTION OUTPUT ;
    USE SIGNAL ;
    PORT
      LAYER met2 ;
        RECT 81.970 0.000 82.250 0.280 ;
    END
  END s_axi_awready
  PIN s_axi_awvalid
    DIRECTION INPUT ;
    USE SIGNAL ;
    ANTENNAGATEAREA 0.647700 ;
    ANTENNADIFFAREA 0.434700 ;
    PORT
      LAYER met3 ;
        RECT 265.265 88.440 265.865 89.040 ;
    END
  END s_axi_awvalid
  PIN s_axi_bready
    DIRECTION INPUT ;
    USE SIGNAL ;
    ANTENNAGATEAREA 0.647700 ;
    ANTENNADIFFAREA 0.434700 ;
    PORT
      LAYER met3 ;
        RECT 265.265 99.320 265.865 99.920 ;
    END
  END s_axi_bready
  PIN s_axi_bresp_0
    DIRECTION OUTPUT ;
    USE SIGNAL ;
    PORT
      LAYER met2 ;
        RECT 82.890 0.000 83.170 0.280 ;
    END
  END s_axi_bresp_0
  PIN s_axi_bresp_1
    DIRECTION OUTPUT ;
    USE SIGNAL ;
    ANTENNAGATEAREA 0.434700 ;
    ANTENNADIFFAREA 1.137600 ;
    PORT
      LAYER met3 ;
        RECT 265.265 96.600 265.865 97.200 ;
    END
  END s_axi_bresp_1
  PIN s_axi_bvalid
    DIRECTION OUTPUT ;
    USE SIGNAL ;
    ANTENNAGATEAREA 0.434700 ;
    ANTENNADIFFAREA 1.137600 ;
    PORT
      LAYER met3 ;
        RECT 265.265 100.680 265.865 101.280 ;
    END
  END s_axi_bvalid
  PIN s_axi_rdata_0
    DIRECTION OUTPUT ;
    USE SIGNAL ;
    ANTENNAGATEAREA 0.434700 ;
    ANTENNADIFFAREA 1.137600 ;
    PORT
      LAYER met2 ;
        RECT 149.130 0.000 149.410 0.280 ;
    END
  END s_axi_rdata_0
  PIN s_axi_rdata_1
    DIRECTION OUTPUT ;
    USE SIGNAL ;
    ANTENNAGATEAREA 0.434700 ;
    ANTENNADIFFAREA 1.137600 ;
    PORT
      LAYER met2 ;
        RECT 190.530 0.000 190.810 0.280 ;
    END
  END s_axi_rdata_1
  PIN s_axi_rdata_10
    DIRECTION OUTPUT ;
    USE SIGNAL ;
    ANTENNAGATEAREA 0.434700 ;
    ANTENNADIFFAREA 1.137600 ;
    PORT
      LAYER met2 ;
        RECT 156.490 0.000 156.770 0.280 ;
    END
  END s_axi_rdata_10
  PIN s_axi_rdata_11
    DIRECTION OUTPUT ;
    USE SIGNAL ;
    ANTENNAGATEAREA 0.434700 ;
    ANTENNADIFFAREA 1.137600 ;
    PORT
      LAYER met2 ;
        RECT 139.010 0.000 139.290 0.280 ;
    END
  END s_axi_rdata_11
  PIN s_axi_rdata_12
    DIRECTION OUTPUT ;
    USE SIGNAL ;
    ANTENNAGATEAREA 0.434700 ;
    ANTENNADIFFAREA 1.137600 ;
    PORT
      LAYER met2 ;
        RECT 142.690 0.000 142.970 0.280 ;
    END
  END s_axi_rdata_12
  PIN s_axi_rdata_13
    DIRECTION OUTPUT ;
    USE SIGNAL ;
    ANTENNAGATEAREA 0.434700 ;
    ANTENNADIFFAREA 1.137600 ;
    PORT
      LAYER met2 ;
        RECT 188.690 0.000 188.970 0.280 ;
    END
  END s_axi_rdata_13
  PIN s_axi_rdata_14
    DIRECTION OUTPUT ;
    USE SIGNAL ;
    PORT
      LAYER met2 ;
        RECT 83.810 0.000 84.090 0.280 ;
    END
  END s_axi_rdata_14
  PIN s_axi_rdata_15
    DIRECTION OUTPUT ;
    USE SIGNAL ;
    ANTENNAGATEAREA 0.434700 ;
    ANTENNADIFFAREA 1.137600 ;
    PORT
      LAYER met2 ;
        RECT 140.850 0.000 141.130 0.280 ;
    END
  END s_axi_rdata_15
  PIN s_axi_rdata_16
    DIRECTION OUTPUT ;
    USE SIGNAL ;
    ANTENNAGATEAREA 0.434700 ;
    ANTENNADIFFAREA 1.137600 ;
    PORT
      LAYER met2 ;
        RECT 141.770 0.000 142.050 0.280 ;
    END
  END s_axi_rdata_16
  PIN s_axi_rdata_17
    DIRECTION OUTPUT ;
    USE SIGNAL ;
    PORT
      LAYER met2 ;
        RECT 84.730 0.000 85.010 0.280 ;
    END
  END s_axi_rdata_17
  PIN s_axi_rdata_18
    DIRECTION OUTPUT ;
    USE SIGNAL ;
    ANTENNAGATEAREA 0.434700 ;
    ANTENNADIFFAREA 1.137600 ;
    PORT
      LAYER met2 ;
        RECT 205.250 0.000 205.530 0.280 ;
    END
  END s_axi_rdata_18
  PIN s_axi_rdata_19
    DIRECTION OUTPUT ;
    USE SIGNAL ;
    ANTENNAGATEAREA 0.434700 ;
    ANTENNADIFFAREA 1.137600 ;
    PORT
      LAYER met2 ;
        RECT 204.330 0.000 204.610 0.280 ;
    END
  END s_axi_rdata_19
  PIN s_axi_rdata_2
    DIRECTION OUTPUT ;
    USE SIGNAL ;
    ANTENNAGATEAREA 0.434700 ;
    ANTENNADIFFAREA 1.137600 ;
    PORT
      LAYER met2 ;
        RECT 151.890 0.000 152.170 0.280 ;
    END
  END s_axi_rdata_2
  PIN s_axi_rdata_20
    DIRECTION OUTPUT ;
    USE SIGNAL ;
    PORT
      LAYER met2 ;
        RECT 85.650 0.000 85.930 0.280 ;
    END
  END s_axi_rdata_20
  PIN s_axi_rdata_21
    DIRECTION OUTPUT ;
    USE SIGNAL ;
    ANTENNAGATEAREA 0.434700 ;
    ANTENNADIFFAREA 1.137600 ;
    PORT
      LAYER met2 ;
        RECT 143.610 0.000 143.890 0.280 ;
    END
  END s_axi_rdata_21
  PIN s_axi_rdata_22
    DIRECTION OUTPUT ;
    USE SIGNAL ;
    PORT
      LAYER met2 ;
        RECT 86.570 0.000 86.850 0.280 ;
    END
  END s_axi_rdata_22
  PIN s_axi_rdata_23
    DIRECTION OUTPUT ;
    USE SIGNAL ;
    ANTENNAGATEAREA 0.434700 ;
    ANTENNADIFFAREA 1.137600 ;
    PORT
      LAYER met2 ;
        RECT 139.930 0.000 140.210 0.280 ;
    END
  END s_axi_rdata_23
  PIN s_axi_rdata_24
    DIRECTION OUTPUT ;
    USE SIGNAL ;
    PORT
      LAYER met2 ;
        RECT 87.490 0.000 87.770 0.280 ;
    END
  END s_axi_rdata_24
  PIN s_axi_rdata_25
    DIRECTION OUTPUT ;
    USE SIGNAL ;
    ANTENNAGATEAREA 0.434700 ;
    ANTENNADIFFAREA 1.137600 ;
    PORT
      LAYER met2 ;
        RECT 146.370 0.000 146.650 0.280 ;
    END
  END s_axi_rdata_25
  PIN s_axi_rdata_26
    DIRECTION OUTPUT ;
    USE SIGNAL ;
    ANTENNAGATEAREA 0.434700 ;
    ANTENNADIFFAREA 1.137600 ;
    PORT
      LAYER met2 ;
        RECT 147.290 0.000 147.570 0.280 ;
    END
  END s_axi_rdata_26
  PIN s_axi_rdata_27
    DIRECTION OUTPUT ;
    USE SIGNAL ;
    ANTENNAGATEAREA 0.434700 ;
    ANTENNADIFFAREA 1.137600 ;
    PORT
      LAYER met2 ;
        RECT 193.290 0.000 193.570 0.280 ;
    END
  END s_axi_rdata_27
  PIN s_axi_rdata_28
    DIRECTION OUTPUT ;
    USE SIGNAL ;
    ANTENNAGATEAREA 0.434700 ;
    ANTENNADIFFAREA 1.137600 ;
    PORT
      LAYER met2 ;
        RECT 199.730 0.000 200.010 0.280 ;
    END
  END s_axi_rdata_28
  PIN s_axi_rdata_29
    DIRECTION OUTPUT ;
    USE SIGNAL ;
    PORT
      LAYER met2 ;
        RECT 88.410 0.000 88.690 0.280 ;
    END
  END s_axi_rdata_29
  PIN s_axi_rdata_3
    DIRECTION OUTPUT ;
    USE SIGNAL ;
    ANTENNAGATEAREA 0.434700 ;
    ANTENNADIFFAREA 1.137600 ;
    PORT
      LAYER met2 ;
        RECT 200.650 0.000 200.930 0.280 ;
    END
  END s_axi_rdata_3
  PIN s_axi_rdata_30
    DIRECTION OUTPUT ;
    USE SIGNAL ;
    ANTENNAGATEAREA 0.434700 ;
    ANTENNADIFFAREA 1.137600 ;
    PORT
      LAYER met2 ;
        RECT 201.570 0.000 201.850 0.280 ;
    END
  END s_axi_rdata_30
  PIN s_axi_rdata_31
    DIRECTION OUTPUT ;
    USE SIGNAL ;
    ANTENNAGATEAREA 0.434700 ;
    ANTENNADIFFAREA 1.137600 ;
    PORT
      LAYER met2 ;
        RECT 203.410 0.000 203.690 0.280 ;
    END
  END s_axi_rdata_31
  PIN s_axi_rdata_4
    DIRECTION OUTPUT ;
    USE SIGNAL ;
    PORT
      LAYER met2 ;
        RECT 89.330 0.000 89.610 0.280 ;
    END
  END s_axi_rdata_4
  PIN s_axi_rdata_5
    DIRECTION OUTPUT ;
    USE SIGNAL ;
    ANTENNAGATEAREA 0.434700 ;
    ANTENNADIFFAREA 1.137600 ;
    PORT
      LAYER met2 ;
        RECT 144.530 0.000 144.810 0.280 ;
    END
  END s_axi_rdata_5
  PIN s_axi_rdata_6
    DIRECTION OUTPUT ;
    USE SIGNAL ;
    ANTENNAGATEAREA 0.434700 ;
    ANTENNADIFFAREA 1.137600 ;
    PORT
      LAYER met2 ;
        RECT 148.210 0.000 148.490 0.280 ;
    END
  END s_axi_rdata_6
  PIN s_axi_rdata_7
    DIRECTION OUTPUT ;
    USE SIGNAL ;
    ANTENNAGATEAREA 0.434700 ;
    ANTENNADIFFAREA 1.137600 ;
    PORT
      LAYER met2 ;
        RECT 189.610 0.000 189.890 0.280 ;
    END
  END s_axi_rdata_7
  PIN s_axi_rdata_8
    DIRECTION OUTPUT ;
    USE SIGNAL ;
    PORT
      LAYER met2 ;
        RECT 90.250 0.000 90.530 0.280 ;
    END
  END s_axi_rdata_8
  PIN s_axi_rdata_9
    DIRECTION OUTPUT ;
    USE SIGNAL ;
    ANTENNAGATEAREA 0.434700 ;
    ANTENNADIFFAREA 1.137600 ;
    PORT
      LAYER met2 ;
        RECT 157.410 0.000 157.690 0.280 ;
    END
  END s_axi_rdata_9
  PIN s_axi_rready
    DIRECTION INPUT ;
    USE SIGNAL ;
    ANTENNAGATEAREA 0.647700 ;
    ANTENNADIFFAREA 0.434700 ;
    PORT
      LAYER met2 ;
        RECT 187.770 0.000 188.050 0.280 ;
    END
  END s_axi_rready
  PIN s_axi_rresp_0
    DIRECTION OUTPUT ;
    USE SIGNAL ;
    PORT
      LAYER met2 ;
        RECT 91.170 0.000 91.450 0.280 ;
    END
  END s_axi_rresp_0
  PIN s_axi_rresp_1
    DIRECTION OUTPUT ;
    USE SIGNAL ;
    PORT
      LAYER met2 ;
        RECT 92.090 0.000 92.370 0.280 ;
    END
  END s_axi_rresp_1
  PIN s_axi_rvalid
    DIRECTION OUTPUT ;
    USE SIGNAL ;
    ANTENNAGATEAREA 0.434700 ;
    ANTENNADIFFAREA 1.137600 ;
    PORT
      LAYER met2 ;
        RECT 194.210 0.000 194.490 0.280 ;
    END
  END s_axi_rvalid
  PIN s_axi_wdata_0
    DIRECTION INPUT ;
    USE SIGNAL ;
    ANTENNAGATEAREA 0.647700 ;
    ANTENNADIFFAREA 0.434700 ;
    PORT
      LAYER met2 ;
        RECT 198.810 0.000 199.090 0.280 ;
    END
  END s_axi_wdata_0
  PIN s_axi_wdata_1
    DIRECTION INPUT ;
    USE SIGNAL ;
    ANTENNAGATEAREA 0.647700 ;
    ANTENNADIFFAREA 0.434700 ;
    PORT
      LAYER met2 ;
        RECT 197.890 0.000 198.170 0.280 ;
    END
  END s_axi_wdata_1
  PIN s_axi_wdata_10
    DIRECTION INPUT ;
    USE SIGNAL ;
    PORT
      LAYER met2 ;
        RECT 93.010 0.000 93.290 0.280 ;
    END
  END s_axi_wdata_10
  PIN s_axi_wdata_11
    DIRECTION INPUT ;
    USE SIGNAL ;
    PORT
      LAYER met2 ;
        RECT 93.930 0.000 94.210 0.280 ;
    END
  END s_axi_wdata_11
  PIN s_axi_wdata_12
    DIRECTION INPUT ;
    USE SIGNAL ;
    PORT
      LAYER met2 ;
        RECT 94.850 0.000 95.130 0.280 ;
    END
  END s_axi_wdata_12
  PIN s_axi_wdata_13
    DIRECTION INPUT ;
    USE SIGNAL ;
    PORT
      LAYER met2 ;
        RECT 95.770 0.000 96.050 0.280 ;
    END
  END s_axi_wdata_13
  PIN s_axi_wdata_14
    DIRECTION INPUT ;
    USE SIGNAL ;
    PORT
      LAYER met2 ;
        RECT 96.690 0.000 96.970 0.280 ;
    END
  END s_axi_wdata_14
  PIN s_axi_wdata_15
    DIRECTION INPUT ;
    USE SIGNAL ;
    PORT
      LAYER met2 ;
        RECT 97.610 0.000 97.890 0.280 ;
    END
  END s_axi_wdata_15
  PIN s_axi_wdata_16
    DIRECTION INPUT ;
    USE SIGNAL ;
    PORT
      LAYER met2 ;
        RECT 98.530 0.000 98.810 0.280 ;
    END
  END s_axi_wdata_16
  PIN s_axi_wdata_17
    DIRECTION INPUT ;
    USE SIGNAL ;
    PORT
      LAYER met2 ;
        RECT 99.450 0.000 99.730 0.280 ;
    END
  END s_axi_wdata_17
  PIN s_axi_wdata_18
    DIRECTION INPUT ;
    USE SIGNAL ;
    PORT
      LAYER met2 ;
        RECT 100.370 0.000 100.650 0.280 ;
    END
  END s_axi_wdata_18
  PIN s_axi_wdata_19
    DIRECTION INPUT ;
    USE SIGNAL ;
    PORT
      LAYER met2 ;
        RECT 101.290 0.000 101.570 0.280 ;
    END
  END s_axi_wdata_19
  PIN s_axi_wdata_2
    DIRECTION INPUT ;
    USE SIGNAL ;
    ANTENNAGATEAREA 0.647700 ;
    ANTENNADIFFAREA 0.434700 ;
    PORT
      LAYER met2 ;
        RECT 195.130 0.000 195.410 0.280 ;
    END
  END s_axi_wdata_2
  PIN s_axi_wdata_20
    DIRECTION INPUT ;
    USE SIGNAL ;
    PORT
      LAYER met2 ;
        RECT 102.210 0.000 102.490 0.280 ;
    END
  END s_axi_wdata_20
  PIN s_axi_wdata_21
    DIRECTION INPUT ;
    USE SIGNAL ;
    PORT
      LAYER met2 ;
        RECT 103.130 0.000 103.410 0.280 ;
    END
  END s_axi_wdata_21
  PIN s_axi_wdata_22
    DIRECTION INPUT ;
    USE SIGNAL ;
    PORT
      LAYER met2 ;
        RECT 104.050 0.000 104.330 0.280 ;
    END
  END s_axi_wdata_22
  PIN s_axi_wdata_23
    DIRECTION INPUT ;
    USE SIGNAL ;
    PORT
      LAYER met2 ;
        RECT 104.970 0.000 105.250 0.280 ;
    END
  END s_axi_wdata_23
  PIN s_axi_wdata_24
    DIRECTION INPUT ;
    USE SIGNAL ;
    PORT
      LAYER met2 ;
        RECT 105.890 0.000 106.170 0.280 ;
    END
  END s_axi_wdata_24
  PIN s_axi_wdata_25
    DIRECTION INPUT ;
    USE SIGNAL ;
    PORT
      LAYER met2 ;
        RECT 106.810 0.000 107.090 0.280 ;
    END
  END s_axi_wdata_25
  PIN s_axi_wdata_26
    DIRECTION INPUT ;
    USE SIGNAL ;
    PORT
      LAYER met2 ;
        RECT 107.730 0.000 108.010 0.280 ;
    END
  END s_axi_wdata_26
  PIN s_axi_wdata_27
    DIRECTION INPUT ;
    USE SIGNAL ;
    PORT
      LAYER met2 ;
        RECT 108.650 0.000 108.930 0.280 ;
    END
  END s_axi_wdata_27
  PIN s_axi_wdata_28
    DIRECTION INPUT ;
    USE SIGNAL ;
    PORT
      LAYER met2 ;
        RECT 109.570 0.000 109.850 0.280 ;
    END
  END s_axi_wdata_28
  PIN s_axi_wdata_29
    DIRECTION INPUT ;
    USE SIGNAL ;
    PORT
      LAYER met2 ;
        RECT 110.490 0.000 110.770 0.280 ;
    END
  END s_axi_wdata_29
  PIN s_axi_wdata_3
    DIRECTION INPUT ;
    USE SIGNAL ;
    ANTENNAGATEAREA 0.647700 ;
    ANTENNADIFFAREA 0.434700 ;
    PORT
      LAYER met3 ;
        RECT 265.265 89.800 265.865 90.400 ;
    END
  END s_axi_wdata_3
  PIN s_axi_wdata_30
    DIRECTION INPUT ;
    USE SIGNAL ;
    PORT
      LAYER met2 ;
        RECT 111.410 0.000 111.690 0.280 ;
    END
  END s_axi_wdata_30
  PIN s_axi_wdata_31
    DIRECTION INPUT ;
    USE SIGNAL ;
    PORT
      LAYER met2 ;
        RECT 112.330 0.000 112.610 0.280 ;
    END
  END s_axi_wdata_31
  PIN s_axi_wdata_4
    DIRECTION INPUT ;
    USE SIGNAL ;
    PORT
      LAYER met2 ;
        RECT 113.250 0.000 113.530 0.280 ;
    END
  END s_axi_wdata_4
  PIN s_axi_wdata_5
    DIRECTION INPUT ;
    USE SIGNAL ;
    PORT
      LAYER met2 ;
        RECT 114.170 0.000 114.450 0.280 ;
    END
  END s_axi_wdata_5
  PIN s_axi_wdata_6
    DIRECTION INPUT ;
    USE SIGNAL ;
    PORT
      LAYER met2 ;
        RECT 115.090 0.000 115.370 0.280 ;
    END
  END s_axi_wdata_6
  PIN s_axi_wdata_7
    DIRECTION INPUT ;
    USE SIGNAL ;
    PORT
      LAYER met2 ;
        RECT 116.010 0.000 116.290 0.280 ;
    END
  END s_axi_wdata_7
  PIN s_axi_wdata_8
    DIRECTION INPUT ;
    USE SIGNAL ;
    PORT
      LAYER met2 ;
        RECT 116.930 0.000 117.210 0.280 ;
    END
  END s_axi_wdata_8
  PIN s_axi_wdata_9
    DIRECTION INPUT ;
    USE SIGNAL ;
    PORT
      LAYER met2 ;
        RECT 117.850 0.000 118.130 0.280 ;
    END
  END s_axi_wdata_9
  PIN s_axi_wready
    DIRECTION OUTPUT ;
    USE SIGNAL ;
    PORT
      LAYER met2 ;
        RECT 118.770 0.000 119.050 0.280 ;
    END
  END s_axi_wready
  PIN s_axi_wstrb_0
    DIRECTION INPUT ;
    USE SIGNAL ;
    ANTENNAGATEAREA 0.647700 ;
    ANTENNADIFFAREA 0.434700 ;
    PORT
      LAYER met2 ;
        RECT 202.490 0.000 202.770 0.280 ;
    END
  END s_axi_wstrb_0
  PIN s_axi_wstrb_1
    DIRECTION INPUT ;
    USE SIGNAL ;
    PORT
      LAYER met2 ;
        RECT 119.690 0.000 119.970 0.280 ;
    END
  END s_axi_wstrb_1
  PIN s_axi_wstrb_2
    DIRECTION INPUT ;
    USE SIGNAL ;
    PORT
      LAYER met2 ;
        RECT 120.610 0.000 120.890 0.280 ;
    END
  END s_axi_wstrb_2
  PIN s_axi_wstrb_3
    DIRECTION INPUT ;
    USE SIGNAL ;
    PORT
      LAYER met2 ;
        RECT 121.530 0.000 121.810 0.280 ;
    END
  END s_axi_wstrb_3
  PIN s_axi_wvalid
    DIRECTION INPUT ;
    USE SIGNAL ;
    ANTENNAGATEAREA 0.647700 ;
    ANTENNADIFFAREA 0.434700 ;
    PORT
      LAYER met3 ;
        RECT 265.265 93.880 265.865 94.480 ;
    END
  END s_axi_wvalid
  OBS
      LAYER nwell ;
        RECT 5.330 10.795 260.090 264.030 ;
      LAYER li1 ;
        RECT 5.520 10.795 259.900 263.925 ;
      LAYER met1 ;
        RECT 5.520 6.160 259.900 264.080 ;
      LAYER met2 ;
        RECT 5.610 276.025 54.090 276.305 ;
        RECT 54.930 276.025 55.010 276.305 ;
        RECT 55.850 276.025 55.930 276.305 ;
        RECT 56.770 276.025 56.850 276.305 ;
        RECT 57.690 276.025 57.770 276.305 ;
        RECT 58.610 276.025 60.530 276.305 ;
        RECT 61.370 276.025 73.410 276.305 ;
        RECT 74.250 276.025 74.330 276.305 ;
        RECT 75.170 276.025 75.250 276.305 ;
        RECT 76.090 276.025 76.170 276.305 ;
        RECT 77.010 276.025 77.090 276.305 ;
        RECT 77.930 276.025 78.010 276.305 ;
        RECT 78.850 276.025 78.930 276.305 ;
        RECT 79.770 276.025 111.130 276.305 ;
        RECT 111.970 276.025 112.050 276.305 ;
        RECT 112.890 276.025 118.490 276.305 ;
        RECT 119.330 276.025 120.330 276.305 ;
        RECT 121.170 276.025 123.090 276.305 ;
        RECT 123.930 276.025 124.010 276.305 ;
        RECT 124.850 276.025 129.530 276.305 ;
        RECT 130.370 276.025 135.970 276.305 ;
        RECT 136.810 276.025 139.650 276.305 ;
        RECT 140.490 276.025 143.330 276.305 ;
        RECT 144.170 276.025 153.450 276.305 ;
        RECT 154.290 276.025 155.290 276.305 ;
        RECT 156.130 276.025 173.690 276.305 ;
        RECT 174.530 276.025 186.570 276.305 ;
        RECT 187.410 276.025 212.330 276.305 ;
        RECT 213.170 276.025 258.430 276.305 ;
        RECT 5.610 0.560 258.430 276.025 ;
        RECT 6.170 0.280 6.250 0.560 ;
        RECT 7.090 0.280 7.170 0.560 ;
        RECT 8.010 0.280 8.090 0.560 ;
        RECT 8.930 0.280 9.010 0.560 ;
        RECT 9.850 0.280 9.930 0.560 ;
        RECT 10.770 0.280 10.850 0.560 ;
        RECT 11.690 0.280 11.770 0.560 ;
        RECT 12.610 0.280 12.690 0.560 ;
        RECT 13.530 0.280 13.610 0.560 ;
        RECT 14.450 0.280 14.530 0.560 ;
        RECT 15.370 0.280 15.450 0.560 ;
        RECT 16.290 0.280 16.370 0.560 ;
        RECT 17.210 0.280 17.290 0.560 ;
        RECT 18.130 0.280 18.210 0.560 ;
        RECT 19.050 0.280 19.130 0.560 ;
        RECT 19.970 0.280 20.050 0.560 ;
        RECT 20.890 0.280 20.970 0.560 ;
        RECT 21.810 0.280 21.890 0.560 ;
        RECT 22.730 0.280 22.810 0.560 ;
        RECT 23.650 0.280 23.730 0.560 ;
        RECT 24.570 0.280 24.650 0.560 ;
        RECT 25.490 0.280 25.570 0.560 ;
        RECT 26.410 0.280 26.490 0.560 ;
        RECT 27.330 0.280 27.410 0.560 ;
        RECT 28.250 0.280 28.330 0.560 ;
        RECT 29.170 0.280 29.250 0.560 ;
        RECT 30.090 0.280 30.170 0.560 ;
        RECT 31.010 0.280 31.090 0.560 ;
        RECT 31.930 0.280 32.010 0.560 ;
        RECT 32.850 0.280 32.930 0.560 ;
        RECT 33.770 0.280 33.850 0.560 ;
        RECT 34.690 0.280 34.770 0.560 ;
        RECT 35.610 0.280 35.690 0.560 ;
        RECT 36.530 0.280 36.610 0.560 ;
        RECT 37.450 0.280 37.530 0.560 ;
        RECT 38.370 0.280 38.450 0.560 ;
        RECT 39.290 0.280 39.370 0.560 ;
        RECT 40.210 0.280 40.290 0.560 ;
        RECT 41.130 0.280 41.210 0.560 ;
        RECT 42.050 0.280 42.130 0.560 ;
        RECT 42.970 0.280 43.050 0.560 ;
        RECT 43.890 0.280 43.970 0.560 ;
        RECT 44.810 0.280 44.890 0.560 ;
        RECT 45.730 0.280 45.810 0.560 ;
        RECT 46.650 0.280 46.730 0.560 ;
        RECT 47.570 0.280 47.650 0.560 ;
        RECT 48.490 0.280 48.570 0.560 ;
        RECT 49.410 0.280 49.490 0.560 ;
        RECT 50.330 0.280 50.410 0.560 ;
        RECT 51.250 0.280 51.330 0.560 ;
        RECT 52.170 0.280 52.250 0.560 ;
        RECT 53.090 0.280 53.170 0.560 ;
        RECT 54.010 0.280 54.090 0.560 ;
        RECT 54.930 0.280 55.010 0.560 ;
        RECT 55.850 0.280 55.930 0.560 ;
        RECT 56.770 0.280 56.850 0.560 ;
        RECT 57.690 0.280 57.770 0.560 ;
        RECT 58.610 0.280 58.690 0.560 ;
        RECT 59.530 0.280 59.610 0.560 ;
        RECT 60.450 0.280 60.530 0.560 ;
        RECT 61.370 0.280 61.450 0.560 ;
        RECT 62.290 0.280 62.370 0.560 ;
        RECT 63.210 0.280 63.290 0.560 ;
        RECT 64.130 0.280 64.210 0.560 ;
        RECT 65.050 0.280 65.130 0.560 ;
        RECT 65.970 0.280 66.050 0.560 ;
        RECT 66.890 0.280 66.970 0.560 ;
        RECT 67.810 0.280 67.890 0.560 ;
        RECT 68.730 0.280 68.810 0.560 ;
        RECT 69.650 0.280 69.730 0.560 ;
        RECT 70.570 0.280 70.650 0.560 ;
        RECT 71.490 0.280 71.570 0.560 ;
        RECT 72.410 0.280 72.490 0.560 ;
        RECT 73.330 0.280 73.410 0.560 ;
        RECT 74.250 0.280 74.330 0.560 ;
        RECT 75.170 0.280 75.250 0.560 ;
        RECT 76.090 0.280 76.170 0.560 ;
        RECT 77.010 0.280 77.090 0.560 ;
        RECT 77.930 0.280 78.010 0.560 ;
        RECT 78.850 0.280 78.930 0.560 ;
        RECT 79.770 0.280 79.850 0.560 ;
        RECT 80.690 0.280 80.770 0.560 ;
        RECT 81.610 0.280 81.690 0.560 ;
        RECT 82.530 0.280 82.610 0.560 ;
        RECT 83.450 0.280 83.530 0.560 ;
        RECT 84.370 0.280 84.450 0.560 ;
        RECT 85.290 0.280 85.370 0.560 ;
        RECT 86.210 0.280 86.290 0.560 ;
        RECT 87.130 0.280 87.210 0.560 ;
        RECT 88.050 0.280 88.130 0.560 ;
        RECT 88.970 0.280 89.050 0.560 ;
        RECT 89.890 0.280 89.970 0.560 ;
        RECT 90.810 0.280 90.890 0.560 ;
        RECT 91.730 0.280 91.810 0.560 ;
        RECT 92.650 0.280 92.730 0.560 ;
        RECT 93.570 0.280 93.650 0.560 ;
        RECT 94.490 0.280 94.570 0.560 ;
        RECT 95.410 0.280 95.490 0.560 ;
        RECT 96.330 0.280 96.410 0.560 ;
        RECT 97.250 0.280 97.330 0.560 ;
        RECT 98.170 0.280 98.250 0.560 ;
        RECT 99.090 0.280 99.170 0.560 ;
        RECT 100.010 0.280 100.090 0.560 ;
        RECT 100.930 0.280 101.010 0.560 ;
        RECT 101.850 0.280 101.930 0.560 ;
        RECT 102.770 0.280 102.850 0.560 ;
        RECT 103.690 0.280 103.770 0.560 ;
        RECT 104.610 0.280 104.690 0.560 ;
        RECT 105.530 0.280 105.610 0.560 ;
        RECT 106.450 0.280 106.530 0.560 ;
        RECT 107.370 0.280 107.450 0.560 ;
        RECT 108.290 0.280 108.370 0.560 ;
        RECT 109.210 0.280 109.290 0.560 ;
        RECT 110.130 0.280 110.210 0.560 ;
        RECT 111.050 0.280 111.130 0.560 ;
        RECT 111.970 0.280 112.050 0.560 ;
        RECT 112.890 0.280 112.970 0.560 ;
        RECT 113.810 0.280 113.890 0.560 ;
        RECT 114.730 0.280 114.810 0.560 ;
        RECT 115.650 0.280 115.730 0.560 ;
        RECT 116.570 0.280 116.650 0.560 ;
        RECT 117.490 0.280 117.570 0.560 ;
        RECT 118.410 0.280 118.490 0.560 ;
        RECT 119.330 0.280 119.410 0.560 ;
        RECT 120.250 0.280 120.330 0.560 ;
        RECT 121.170 0.280 121.250 0.560 ;
        RECT 122.090 0.280 125.850 0.560 ;
        RECT 126.690 0.280 126.770 0.560 ;
        RECT 127.610 0.280 138.730 0.560 ;
        RECT 139.570 0.280 139.650 0.560 ;
        RECT 140.490 0.280 140.570 0.560 ;
        RECT 141.410 0.280 141.490 0.560 ;
        RECT 142.330 0.280 142.410 0.560 ;
        RECT 143.250 0.280 143.330 0.560 ;
        RECT 144.170 0.280 144.250 0.560 ;
        RECT 145.090 0.280 146.090 0.560 ;
        RECT 146.930 0.280 147.010 0.560 ;
        RECT 147.850 0.280 147.930 0.560 ;
        RECT 148.770 0.280 148.850 0.560 ;
        RECT 149.690 0.280 151.610 0.560 ;
        RECT 152.450 0.280 156.210 0.560 ;
        RECT 157.050 0.280 157.130 0.560 ;
        RECT 157.970 0.280 185.650 0.560 ;
        RECT 186.490 0.280 186.570 0.560 ;
        RECT 187.410 0.280 187.490 0.560 ;
        RECT 188.330 0.280 188.410 0.560 ;
        RECT 189.250 0.280 189.330 0.560 ;
        RECT 190.170 0.280 190.250 0.560 ;
        RECT 191.090 0.280 191.170 0.560 ;
        RECT 192.010 0.280 192.090 0.560 ;
        RECT 192.930 0.280 193.010 0.560 ;
        RECT 193.850 0.280 193.930 0.560 ;
        RECT 194.770 0.280 194.850 0.560 ;
        RECT 195.690 0.280 195.770 0.560 ;
        RECT 196.610 0.280 196.690 0.560 ;
        RECT 197.530 0.280 197.610 0.560 ;
        RECT 198.450 0.280 198.530 0.560 ;
        RECT 199.370 0.280 199.450 0.560 ;
        RECT 200.290 0.280 200.370 0.560 ;
        RECT 201.210 0.280 201.290 0.560 ;
        RECT 202.130 0.280 202.210 0.560 ;
        RECT 203.050 0.280 203.130 0.560 ;
        RECT 203.970 0.280 204.050 0.560 ;
        RECT 204.890 0.280 204.970 0.560 ;
        RECT 205.810 0.280 220.610 0.560 ;
        RECT 221.450 0.280 228.890 0.560 ;
        RECT 229.730 0.280 230.730 0.560 ;
        RECT 231.570 0.280 236.250 0.560 ;
        RECT 237.090 0.280 238.090 0.560 ;
        RECT 238.930 0.280 258.430 0.560 ;
      LAYER met3 ;
        RECT 0.600 252.640 265.265 264.005 ;
        RECT 1.000 249.880 265.265 252.640 ;
        RECT 0.600 198.240 265.265 249.880 ;
        RECT 0.600 196.840 264.865 198.240 ;
        RECT 0.600 190.080 265.265 196.840 ;
        RECT 0.600 188.680 264.865 190.080 ;
        RECT 0.600 184.640 265.265 188.680 ;
        RECT 0.600 183.240 264.865 184.640 ;
        RECT 0.600 181.920 265.265 183.240 ;
        RECT 1.000 180.520 265.265 181.920 ;
        RECT 0.600 177.840 265.265 180.520 ;
        RECT 1.000 175.080 265.265 177.840 ;
        RECT 0.600 172.400 265.265 175.080 ;
        RECT 1.000 171.040 265.265 172.400 ;
        RECT 1.000 171.000 264.865 171.040 ;
        RECT 0.600 169.640 264.865 171.000 ;
        RECT 0.600 168.320 265.265 169.640 ;
        RECT 0.600 165.560 264.865 168.320 ;
        RECT 0.600 164.240 265.265 165.560 ;
        RECT 1.000 162.840 265.265 164.240 ;
        RECT 0.600 158.800 265.265 162.840 ;
        RECT 0.600 157.400 264.865 158.800 ;
        RECT 0.600 152.000 265.265 157.400 ;
        RECT 1.000 149.280 265.265 152.000 ;
        RECT 1.000 146.520 264.865 149.280 ;
        RECT 0.600 143.840 265.265 146.520 ;
        RECT 0.600 142.440 264.865 143.840 ;
        RECT 0.600 134.320 265.265 142.440 ;
        RECT 0.600 130.200 264.865 134.320 ;
        RECT 0.600 113.920 265.265 130.200 ;
        RECT 0.600 108.440 264.865 113.920 ;
        RECT 0.600 107.120 265.265 108.440 ;
        RECT 0.600 105.720 264.865 107.120 ;
        RECT 0.600 101.680 265.265 105.720 ;
        RECT 0.600 98.920 264.865 101.680 ;
        RECT 0.600 97.600 265.265 98.920 ;
        RECT 0.600 96.200 264.865 97.600 ;
        RECT 0.600 94.880 265.265 96.200 ;
        RECT 0.600 93.480 264.865 94.880 ;
        RECT 0.600 90.800 265.265 93.480 ;
        RECT 0.600 88.040 264.865 90.800 ;
        RECT 0.600 8.335 265.265 88.040 ;
      LAYER met4 ;
        RECT 173.255 13.095 174.240 188.185 ;
        RECT 176.640 13.095 177.540 188.185 ;
        RECT 179.940 13.095 199.345 188.185 ;
  END
END mbist_ctrl
END LIBRARY

